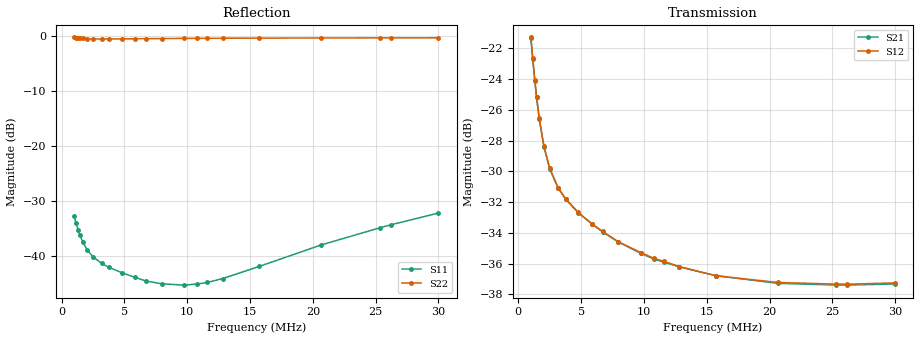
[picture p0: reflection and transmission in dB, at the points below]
! ListType=Log
!!FT140-43 7T CMF
# MHZ S RI R 50
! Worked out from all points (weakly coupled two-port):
!   101 points, 1 MHz to 30 MHz, reference 50 ohm
!   highest |S21| = -21.29 dB at 1 MHz (marker M1); lowest = -37.4 dB at 26.18 MHz (marker M2)
!   lowest |S11| = -45.3 dB at 9.765 MHz (marker M3), VSWR 1.01, Z = 50.3 + j0.484 ohm
!   |S11| at or under -10 dB: start of sweep to end of sweep
!   |S22| runs from -0.5 to -0.3 dB; largest |S21 - S12| = 0.0003
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1  -0.00309 0.0228  0.0118 -0.0854  0.0119 -0.0855  0.9084 0.3447
1.145737  -0.00265 0.0198  0.0105 -0.0729  0.0106 -0.0731  0.9199 0.2961
1.312713  -0.00243 0.0171  0.01 -0.0617  0.0102 -0.0619  0.9259 0.2542
1.453729  -0.00241 0.0153  0.0103 -0.0542  0.0104 -0.0543  0.9283 0.227
1.66559  -0.00253 0.0133  0.0113 -0.0455  0.0114 -0.0457  0.9298 0.1962
2.042657  -0.00268 0.011  0.0133 -0.0356  0.0134 -0.0358  0.9306 0.1595
2.505087  -0.00277 0.00944  0.015 -0.0285  0.015 -0.0287  0.9314 0.1315
3.178493  -0.00258 0.0082  0.0162 -0.0227  0.0162 -0.0228  0.9333 0.1066
3.767708  -0.00228 0.00757  0.0166 -0.0196  0.0167 -0.0197  0.9354 0.0923
4.780527  -0.00156 0.0069  0.0166 -0.0162  0.0167 -0.0162  0.9389 0.0755
5.862773  -0.000693 0.00636  0.0163 -0.0138  0.0163 -0.0138  0.9423 0.0631
6.717194  2.31e-05 0.00594  0.0159 -0.0123  0.016 -0.0123  0.9445 0.0557
7.9624  0.00105 0.0055  0.0154 -0.0105  0.0154 -0.0106  0.9471 0.0471
9.764977  0.00256 0.00481  0.0148 -0.00862  0.0149 -0.00863  0.9502 0.0377
10.81396  0.00346 0.00438  0.0145 -0.00767  0.0146 -0.00768  0.9516 0.0332
11.57517  0.00412 0.00402  0.0144 -0.00708  0.0145 -0.0071  0.9525 0.0302
12.81861  0.0052 0.00346  0.0142 -0.00619  0.0142 -0.00623  0.9538 0.0259
15.72057  0.00783 0.00188  0.0138 -0.00443  0.0138 -0.00443  0.9564 0.0173
20.63659  0.0125 -0.00159  0.0135 -0.00224  0.0136 -0.0022  0.9594 0.00564
25.30843  0.017 -0.00606  0.0135 -0.000548  0.0136 -0.00047  0.9612 -0.0035
26.18402  0.0179 -0.00702  0.0135 -0.000342  0.0136 -0.000245  0.9614 -0.00526
30  0.0216 -0.0118  0.0136 0.000768  0.0137 0.000884  0.9626 -0.0117
